VERSION 5.7 ;
BUSBITCHARS "[]" ;
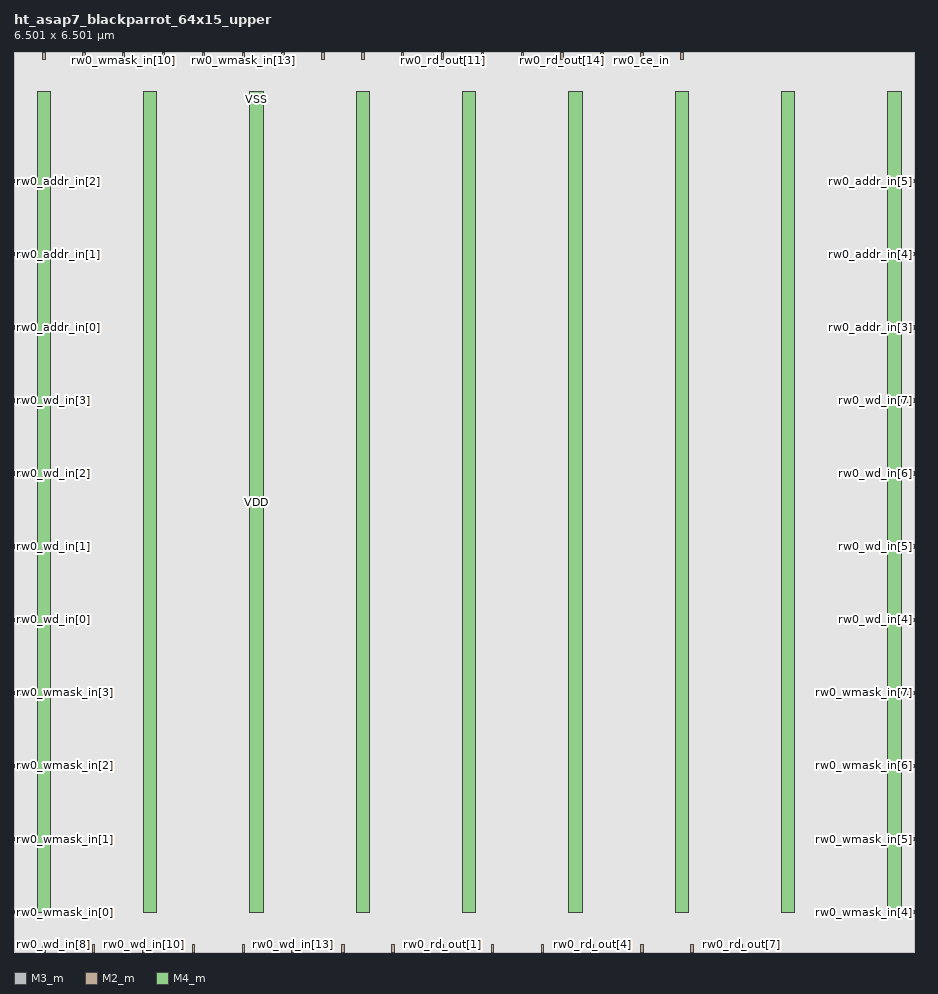
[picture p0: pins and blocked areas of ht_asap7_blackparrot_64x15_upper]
MACRO ht_asap7_blackparrot_64x15_upper
  FOREIGN ht_asap7_blackparrot_64x15_upper 0 0 ;
  SYMMETRY X Y R90 ;
  SIZE 6.501 BY 6.501 ;
  CLASS BLOCK ;
  PIN rw0_wmask_in[0]
    DIRECTION INPUT ;
    USE SIGNAL ;
    SHAPE ABUTMENT ;
    PORT
      LAYER M3_m ;
      RECT 0.000 0.276 0.072 0.300 ;
    END
  END rw0_wmask_in[0]
  PIN rw0_wmask_in[1]
    DIRECTION INPUT ;
    USE SIGNAL ;
    SHAPE ABUTMENT ;
    PORT
      LAYER M3_m ;
      RECT 0.000 0.804 0.072 0.828 ;
    END
  END rw0_wmask_in[1]
  PIN rw0_wmask_in[2]
    DIRECTION INPUT ;
    USE SIGNAL ;
    SHAPE ABUTMENT ;
    PORT
      LAYER M3_m ;
      RECT 0.000 1.332 0.072 1.356 ;
    END
  END rw0_wmask_in[2]
  PIN rw0_wmask_in[3]
    DIRECTION INPUT ;
    USE SIGNAL ;
    SHAPE ABUTMENT ;
    PORT
      LAYER M3_m ;
      RECT 0.000 1.860 0.072 1.884 ;
    END
  END rw0_wmask_in[3]
  PIN rw0_wmask_in[4]
    DIRECTION INPUT ;
    USE SIGNAL ;
    SHAPE ABUTMENT ;
    PORT
      LAYER M3_m ;
      RECT 6.429 0.276 6.501 0.300 ;
    END
  END rw0_wmask_in[4]
  PIN rw0_wmask_in[5]
    DIRECTION INPUT ;
    USE SIGNAL ;
    SHAPE ABUTMENT ;
    PORT
      LAYER M3_m ;
      RECT 6.429 0.804 6.501 0.828 ;
    END
  END rw0_wmask_in[5]
  PIN rw0_wmask_in[6]
    DIRECTION INPUT ;
    USE SIGNAL ;
    SHAPE ABUTMENT ;
    PORT
      LAYER M3_m ;
      RECT 6.429 1.332 6.501 1.356 ;
    END
  END rw0_wmask_in[6]
  PIN rw0_wmask_in[7]
    DIRECTION INPUT ;
    USE SIGNAL ;
    SHAPE ABUTMENT ;
    PORT
      LAYER M3_m ;
      RECT 6.429 1.860 6.501 1.884 ;
    END
  END rw0_wmask_in[7]
  PIN rw0_wmask_in[8]
    DIRECTION INPUT ;
    USE SIGNAL ;
    SHAPE ABUTMENT ;
    PORT
      LAYER M2_m ;
      RECT 0.207 6.447 0.225 6.501 ;
    END
  END rw0_wmask_in[8]
  PIN rw0_wmask_in[9]
    DIRECTION INPUT ;
    USE SIGNAL ;
    SHAPE ABUTMENT ;
    PORT
      LAYER M2_m ;
      RECT 0.495 6.447 0.513 6.501 ;
    END
  END rw0_wmask_in[9]
  PIN rw0_wmask_in[10]
    DIRECTION INPUT ;
    USE SIGNAL ;
    SHAPE ABUTMENT ;
    PORT
      LAYER M2_m ;
      RECT 0.783 6.447 0.801 6.501 ;
    END
  END rw0_wmask_in[10]
  PIN rw0_wmask_in[11]
    DIRECTION INPUT ;
    USE SIGNAL ;
    SHAPE ABUTMENT ;
    PORT
      LAYER M2_m ;
      RECT 1.071 6.447 1.089 6.501 ;
    END
  END rw0_wmask_in[11]
  PIN rw0_wmask_in[12]
    DIRECTION INPUT ;
    USE SIGNAL ;
    SHAPE ABUTMENT ;
    PORT
      LAYER M2_m ;
      RECT 1.359 6.447 1.377 6.501 ;
    END
  END rw0_wmask_in[12]
  PIN rw0_wmask_in[13]
    DIRECTION INPUT ;
    USE SIGNAL ;
    SHAPE ABUTMENT ;
    PORT
      LAYER M2_m ;
      RECT 1.647 6.447 1.665 6.501 ;
    END
  END rw0_wmask_in[13]
  PIN rw0_wmask_in[14]
    DIRECTION INPUT ;
    USE SIGNAL ;
    SHAPE ABUTMENT ;
    PORT
      LAYER M2_m ;
      RECT 1.935 6.447 1.953 6.501 ;
    END
  END rw0_wmask_in[14]
  PIN rw0_wd_in[0]
    DIRECTION INPUT ;
    USE SIGNAL ;
    SHAPE ABUTMENT ;
    PORT
      LAYER M3_m ;
      RECT 0.000 2.388 0.072 2.412 ;
    END
  END rw0_wd_in[0]
  PIN rw0_wd_in[1]
    DIRECTION INPUT ;
    USE SIGNAL ;
    SHAPE ABUTMENT ;
    PORT
      LAYER M3_m ;
      RECT 0.000 2.916 0.072 2.940 ;
    END
  END rw0_wd_in[1]
  PIN rw0_wd_in[2]
    DIRECTION INPUT ;
    USE SIGNAL ;
    SHAPE ABUTMENT ;
    PORT
      LAYER M3_m ;
      RECT 0.000 3.444 0.072 3.468 ;
    END
  END rw0_wd_in[2]
  PIN rw0_wd_in[3]
    DIRECTION INPUT ;
    USE SIGNAL ;
    SHAPE ABUTMENT ;
    PORT
      LAYER M3_m ;
      RECT 0.000 3.972 0.072 3.996 ;
    END
  END rw0_wd_in[3]
  PIN rw0_wd_in[4]
    DIRECTION INPUT ;
    USE SIGNAL ;
    SHAPE ABUTMENT ;
    PORT
      LAYER M3_m ;
      RECT 6.429 2.388 6.501 2.412 ;
    END
  END rw0_wd_in[4]
  PIN rw0_wd_in[5]
    DIRECTION INPUT ;
    USE SIGNAL ;
    SHAPE ABUTMENT ;
    PORT
      LAYER M3_m ;
      RECT 6.429 2.916 6.501 2.940 ;
    END
  END rw0_wd_in[5]
  PIN rw0_wd_in[6]
    DIRECTION INPUT ;
    USE SIGNAL ;
    SHAPE ABUTMENT ;
    PORT
      LAYER M3_m ;
      RECT 6.429 3.444 6.501 3.468 ;
    END
  END rw0_wd_in[6]
  PIN rw0_wd_in[7]
    DIRECTION INPUT ;
    USE SIGNAL ;
    SHAPE ABUTMENT ;
    PORT
      LAYER M3_m ;
      RECT 6.429 3.972 6.501 3.996 ;
    END
  END rw0_wd_in[7]
  PIN rw0_wd_in[8]
    DIRECTION INPUT ;
    USE SIGNAL ;
    SHAPE ABUTMENT ;
    PORT
      LAYER M2_m ;
      RECT 0.207 0.000 0.225 0.054 ;
    END
  END rw0_wd_in[8]
  PIN rw0_wd_in[9]
    DIRECTION INPUT ;
    USE SIGNAL ;
    SHAPE ABUTMENT ;
    PORT
      LAYER M2_m ;
      RECT 0.567 0.000 0.585 0.054 ;
    END
  END rw0_wd_in[9]
  PIN rw0_wd_in[10]
    DIRECTION INPUT ;
    USE SIGNAL ;
    SHAPE ABUTMENT ;
    PORT
      LAYER M2_m ;
      RECT 0.927 0.000 0.945 0.054 ;
    END
  END rw0_wd_in[10]
  PIN rw0_wd_in[11]
    DIRECTION INPUT ;
    USE SIGNAL ;
    SHAPE ABUTMENT ;
    PORT
      LAYER M2_m ;
      RECT 1.287 0.000 1.305 0.054 ;
    END
  END rw0_wd_in[11]
  PIN rw0_wd_in[12]
    DIRECTION INPUT ;
    USE SIGNAL ;
    SHAPE ABUTMENT ;
    PORT
      LAYER M2_m ;
      RECT 1.647 0.000 1.665 0.054 ;
    END
  END rw0_wd_in[12]
  PIN rw0_wd_in[13]
    DIRECTION INPUT ;
    USE SIGNAL ;
    SHAPE ABUTMENT ;
    PORT
      LAYER M2_m ;
      RECT 2.007 0.000 2.025 0.054 ;
    END
  END rw0_wd_in[13]
  PIN rw0_wd_in[14]
    DIRECTION INPUT ;
    USE SIGNAL ;
    SHAPE ABUTMENT ;
    PORT
      LAYER M2_m ;
      RECT 2.367 0.000 2.385 0.054 ;
    END
  END rw0_wd_in[14]
  PIN rw0_rd_out[0]
    DIRECTION OUTPUT ;
    USE SIGNAL ;
    SHAPE ABUTMENT ;
    PORT
      LAYER M2_m ;
      RECT 2.727 0.000 2.745 0.054 ;
    END
  END rw0_rd_out[0]
  PIN rw0_rd_out[1]
    DIRECTION OUTPUT ;
    USE SIGNAL ;
    SHAPE ABUTMENT ;
    PORT
      LAYER M2_m ;
      RECT 3.087 0.000 3.105 0.054 ;
    END
  END rw0_rd_out[1]
  PIN rw0_rd_out[2]
    DIRECTION OUTPUT ;
    USE SIGNAL ;
    SHAPE ABUTMENT ;
    PORT
      LAYER M2_m ;
      RECT 3.447 0.000 3.465 0.054 ;
    END
  END rw0_rd_out[2]
  PIN rw0_rd_out[3]
    DIRECTION OUTPUT ;
    USE SIGNAL ;
    SHAPE ABUTMENT ;
    PORT
      LAYER M2_m ;
      RECT 3.807 0.000 3.825 0.054 ;
    END
  END rw0_rd_out[3]
  PIN rw0_rd_out[4]
    DIRECTION OUTPUT ;
    USE SIGNAL ;
    SHAPE ABUTMENT ;
    PORT
      LAYER M2_m ;
      RECT 4.167 0.000 4.185 0.054 ;
    END
  END rw0_rd_out[4]
  PIN rw0_rd_out[5]
    DIRECTION OUTPUT ;
    USE SIGNAL ;
    SHAPE ABUTMENT ;
    PORT
      LAYER M2_m ;
      RECT 4.527 0.000 4.545 0.054 ;
    END
  END rw0_rd_out[5]
  PIN rw0_rd_out[6]
    DIRECTION OUTPUT ;
    USE SIGNAL ;
    SHAPE ABUTMENT ;
    PORT
      LAYER M2_m ;
      RECT 4.887 0.000 4.905 0.054 ;
    END
  END rw0_rd_out[6]
  PIN rw0_rd_out[7]
    DIRECTION OUTPUT ;
    USE SIGNAL ;
    SHAPE ABUTMENT ;
    PORT
      LAYER M2_m ;
      RECT 5.247 0.000 5.265 0.054 ;
    END
  END rw0_rd_out[7]
  PIN rw0_rd_out[8]
    DIRECTION OUTPUT ;
    USE SIGNAL ;
    SHAPE ABUTMENT ;
    PORT
      LAYER M2_m ;
      RECT 2.223 6.447 2.241 6.501 ;
    END
  END rw0_rd_out[8]
  PIN rw0_rd_out[9]
    DIRECTION OUTPUT ;
    USE SIGNAL ;
    SHAPE ABUTMENT ;
    PORT
      LAYER M2_m ;
      RECT 2.511 6.447 2.529 6.501 ;
    END
  END rw0_rd_out[9]
  PIN rw0_rd_out[10]
    DIRECTION OUTPUT ;
    USE SIGNAL ;
    SHAPE ABUTMENT ;
    PORT
      LAYER M2_m ;
      RECT 2.799 6.447 2.817 6.501 ;
    END
  END rw0_rd_out[10]
  PIN rw0_rd_out[11]
    DIRECTION OUTPUT ;
    USE SIGNAL ;
    SHAPE ABUTMENT ;
    PORT
      LAYER M2_m ;
      RECT 3.087 6.447 3.105 6.501 ;
    END
  END rw0_rd_out[11]
  PIN rw0_rd_out[12]
    DIRECTION OUTPUT ;
    USE SIGNAL ;
    SHAPE ABUTMENT ;
    PORT
      LAYER M2_m ;
      RECT 3.375 6.447 3.393 6.501 ;
    END
  END rw0_rd_out[12]
  PIN rw0_rd_out[13]
    DIRECTION OUTPUT ;
    USE SIGNAL ;
    SHAPE ABUTMENT ;
    PORT
      LAYER M2_m ;
      RECT 3.663 6.447 3.681 6.501 ;
    END
  END rw0_rd_out[13]
  PIN rw0_rd_out[14]
    DIRECTION OUTPUT ;
    USE SIGNAL ;
    SHAPE ABUTMENT ;
    PORT
      LAYER M2_m ;
      RECT 3.951 6.447 3.969 6.501 ;
    END
  END rw0_rd_out[14]
  PIN rw0_addr_in[0]
    DIRECTION INPUT ;
    USE SIGNAL ;
    SHAPE ABUTMENT ;
    PORT
      LAYER M3_m ;
      RECT 0.000 4.500 0.072 4.524 ;
    END
  END rw0_addr_in[0]
  PIN rw0_addr_in[1]
    DIRECTION INPUT ;
    USE SIGNAL ;
    SHAPE ABUTMENT ;
    PORT
      LAYER M3_m ;
      RECT 0.000 5.028 0.072 5.052 ;
    END
  END rw0_addr_in[1]
  PIN rw0_addr_in[2]
    DIRECTION INPUT ;
    USE SIGNAL ;
    SHAPE ABUTMENT ;
    PORT
      LAYER M3_m ;
      RECT 0.000 5.556 0.072 5.580 ;
    END
  END rw0_addr_in[2]
  PIN rw0_addr_in[3]
    DIRECTION INPUT ;
    USE SIGNAL ;
    SHAPE ABUTMENT ;
    PORT
      LAYER M3_m ;
      RECT 6.429 4.500 6.501 4.524 ;
    END
  END rw0_addr_in[3]
  PIN rw0_addr_in[4]
    DIRECTION INPUT ;
    USE SIGNAL ;
    SHAPE ABUTMENT ;
    PORT
      LAYER M3_m ;
      RECT 6.429 5.028 6.501 5.052 ;
    END
  END rw0_addr_in[4]
  PIN rw0_addr_in[5]
    DIRECTION INPUT ;
    USE SIGNAL ;
    SHAPE ABUTMENT ;
    PORT
      LAYER M3_m ;
      RECT 6.429 5.556 6.501 5.580 ;
    END
  END rw0_addr_in[5]
  PIN rw0_we_in
    DIRECTION INPUT ;
    USE SIGNAL ;
    SHAPE ABUTMENT ;
    PORT
      LAYER M2_m ;
      RECT 4.239 6.447 4.257 6.501 ;
    END
  END rw0_we_in
  PIN rw0_ce_in
    DIRECTION INPUT ;
    USE SIGNAL ;
    SHAPE ABUTMENT ;
    PORT
      LAYER M2_m ;
      RECT 4.527 6.447 4.545 6.501 ;
    END
  END rw0_ce_in
  PIN rw0_clk
    DIRECTION INPUT ;
    USE SIGNAL ;
    SHAPE ABUTMENT ;
    PORT
      LAYER M2_m ;
      RECT 4.815 6.447 4.833 6.501 ;
    END
  END rw0_clk
  PIN VSS
    DIRECTION INOUT ;
    USE GROUND ;
    PORT
      LAYER M4_m ;
      RECT 0.168 0.288 0.264 6.213 ;
      RECT 0.936 0.288 1.032 6.213 ;
      RECT 1.704 0.288 1.800 6.213 ;
      RECT 2.472 0.288 2.568 6.213 ;
      RECT 3.240 0.288 3.336 6.213 ;
      RECT 4.008 0.288 4.104 6.213 ;
      RECT 4.776 0.288 4.872 6.213 ;
      RECT 5.544 0.288 5.640 6.213 ;
      RECT 6.312 0.288 6.408 6.213 ;
    END
  END VSS
  PIN VDD
    DIRECTION INOUT ;
    USE POWER ;
    PORT
      LAYER M4_m ;
      RECT 0.168 0.288 0.264 6.213 ;
      RECT 0.936 0.288 1.032 6.213 ;
      RECT 1.704 0.288 1.800 6.213 ;
      RECT 2.472 0.288 2.568 6.213 ;
      RECT 3.240 0.288 3.336 6.213 ;
      RECT 4.008 0.288 4.104 6.213 ;
      RECT 4.776 0.288 4.872 6.213 ;
      RECT 5.544 0.288 5.640 6.213 ;
      RECT 6.312 0.288 6.408 6.213 ;
    END
  END VDD
  OBS
    LAYER M1_m ;
    RECT 0 0 6.501 6.501 ;
    LAYER M2_m ;
    RECT 0 0 6.501 6.501 ;
    LAYER M3_m ;
    RECT 0 0 6.501 6.501 ;
    LAYER M4_m ;
    RECT 0 0 6.501 6.501 ;
  END
END ht_asap7_blackparrot_64x15_upper

END LIBRARY
